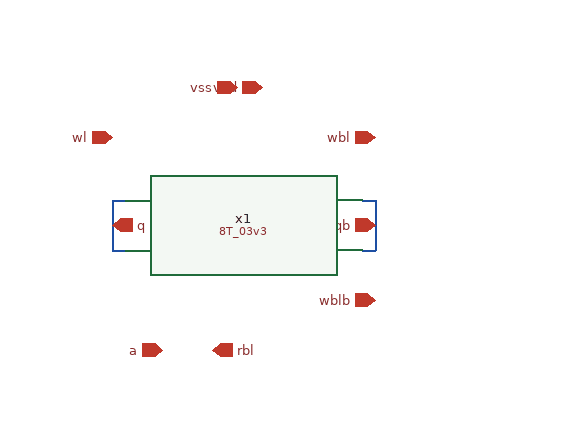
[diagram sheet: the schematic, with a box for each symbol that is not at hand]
v {xschem version=3.4.8RC file_version=1.3}
G {}
K {}
V {}
S {}
F {}
E {}
N 740 -280 740 -240 {lab=qb}
N 730 -240 740 -240 {lab=qb}
N 730 -280 740 -280 {lab=qb}
N 530 -280 530 -240 {lab=q}
N 530 -240 540 -240 {lab=q}
N 530 -280 540 -280 {lab=q}
C {ipin.sym} 650 -370 1 0 {name=p1 lab=vdd}
C {ipin.sym} 630 -370 1 0 {name=p2 lab=vss}
C {ipin.sym} 530 -330 0 0 {name=p4 lab=wl}
C {opin.sym} 530 -260 2 0 {name=p5 lab=q}
C {opin.sym} 740 -260 2 1 {name=p6 lab=qb}
C {ipin.sym} 570 -160 3 0 {name=p7 lab=a}
C {opin.sym} 610 -160 1 0 {name=p8 lab=rbl}
C {ipin.sym} 740 -330 2 0 {name=p3 lab=wbl}
C {ipin.sym} 740 -200 2 0 {name=p9 lab=wblb}
C {title.sym} 180 -40 0 0 {name=l1 author="Ratish V. Gupta"}
C {/workspace/analog/designs/8T_03v3.sym} 635 -260 0 0 {name=x1}
